VERSION 5.7 ;
  NOWIREEXTENSIONATPIN ON ;
  DIVIDERCHAR "/" ;
  BUSBITCHARS "[]" ;
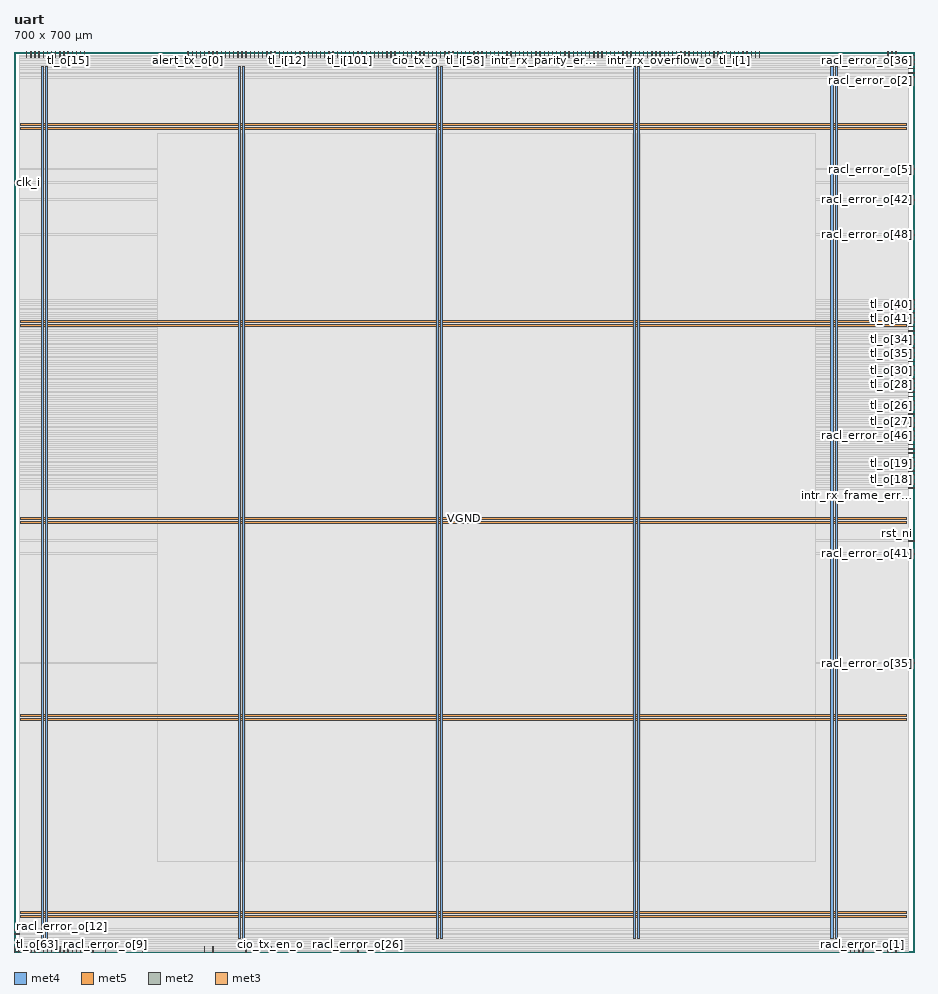
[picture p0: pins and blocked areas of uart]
MACRO uart
  CLASS BLOCK ;
  FOREIGN uart ;
  ORIGIN 0.000 0.000 ;
  SIZE 700.000 BY 700.000 ;
  PIN VGND
    DIRECTION INOUT ;
    USE GROUND ;
    PORT
      LAYER met4 ;
        RECT 24.340 10.640 25.940 688.400 ;
    END
    PORT
      LAYER met4 ;
        RECT 177.940 10.640 179.540 688.400 ;
    END
    PORT
      LAYER met4 ;
        RECT 331.540 10.640 333.140 688.400 ;
    END
    PORT
      LAYER met4 ;
        RECT 485.140 10.640 486.740 688.400 ;
    END
    PORT
      LAYER met4 ;
        RECT 638.740 10.640 640.340 688.400 ;
    END
    PORT
      LAYER met5 ;
        RECT 5.280 30.030 694.380 31.630 ;
    END
    PORT
      LAYER met5 ;
        RECT 5.280 183.210 694.380 184.810 ;
    END
    PORT
      LAYER met5 ;
        RECT 5.280 336.390 694.380 337.990 ;
    END
    PORT
      LAYER met5 ;
        RECT 5.280 489.570 694.380 491.170 ;
    END
    PORT
      LAYER met5 ;
        RECT 5.280 642.750 694.380 644.350 ;
    END
  END VGND
  PIN VPWR
    DIRECTION INOUT ;
    USE POWER ;
    PORT
      LAYER met4 ;
        RECT 21.040 10.640 22.640 688.400 ;
    END
    PORT
      LAYER met4 ;
        RECT 174.640 10.640 176.240 688.400 ;
    END
    PORT
      LAYER met4 ;
        RECT 328.240 10.640 329.840 688.400 ;
    END
    PORT
      LAYER met4 ;
        RECT 481.840 10.640 483.440 688.400 ;
    END
    PORT
      LAYER met4 ;
        RECT 635.440 10.640 637.040 688.400 ;
    END
    PORT
      LAYER met5 ;
        RECT 5.280 26.730 694.380 28.330 ;
    END
    PORT
      LAYER met5 ;
        RECT 5.280 179.910 694.380 181.510 ;
    END
    PORT
      LAYER met5 ;
        RECT 5.280 333.090 694.380 334.690 ;
    END
    PORT
      LAYER met5 ;
        RECT 5.280 486.270 694.380 487.870 ;
    END
    PORT
      LAYER met5 ;
        RECT 5.280 639.450 694.380 641.050 ;
    END
  END VPWR
  PIN alert_rx_i[0]
    DIRECTION INPUT ;
    USE SIGNAL ;
    ANTENNAGATEAREA 0.631200 ;
    ANTENNADIFFAREA 0.434700 ;
    PORT
      LAYER met2 ;
        RECT 19.410 696.000 19.690 700.000 ;
    END
  END alert_rx_i[0]
  PIN alert_rx_i[1]
    DIRECTION INPUT ;
    USE SIGNAL ;
    ANTENNAGATEAREA 0.631200 ;
    ANTENNADIFFAREA 0.434700 ;
    PORT
      LAYER met2 ;
        RECT 45.170 696.000 45.450 700.000 ;
    END
  END alert_rx_i[1]
  PIN alert_rx_i[2]
    DIRECTION INPUT ;
    USE SIGNAL ;
    ANTENNAGATEAREA 0.631200 ;
    ANTENNADIFFAREA 0.434700 ;
    PORT
      LAYER met2 ;
        RECT 54.830 696.000 55.110 700.000 ;
    END
  END alert_rx_i[2]
  PIN alert_rx_i[3]
    DIRECTION INPUT ;
    USE SIGNAL ;
    ANTENNAGATEAREA 0.631200 ;
    ANTENNADIFFAREA 0.434700 ;
    PORT
      LAYER met2 ;
        RECT 35.510 696.000 35.790 700.000 ;
    END
  END alert_rx_i[3]
  PIN alert_tx_o[0]
    DIRECTION OUTPUT ;
    USE SIGNAL ;
    ANTENNADIFFAREA 0.445500 ;
    PORT
      LAYER met2 ;
        RECT 135.330 696.000 135.610 700.000 ;
    END
  END alert_tx_o[0]
  PIN alert_tx_o[1]
    DIRECTION OUTPUT ;
    USE SIGNAL ;
    ANTENNADIFFAREA 0.445500 ;
    PORT
      LAYER met2 ;
        RECT 154.650 696.000 154.930 700.000 ;
    END
  END alert_tx_o[1]
  PIN cio_rx_i
    DIRECTION INPUT ;
    USE SIGNAL ;
    ANTENNAGATEAREA 0.647700 ;
    ANTENNADIFFAREA 0.434700 ;
    PORT
      LAYER met2 ;
        RECT 228.710 696.000 228.990 700.000 ;
    END
  END cio_rx_i
  PIN cio_tx_en_o
    DIRECTION OUTPUT ;
    USE SIGNAL ;
    PORT
      LAYER met2 ;
        RECT 199.730 0.000 200.010 4.000 ;
    END
  END cio_tx_en_o
  PIN cio_tx_o
    DIRECTION OUTPUT ;
    USE SIGNAL ;
    ANTENNADIFFAREA 0.445500 ;
    PORT
      LAYER met2 ;
        RECT 312.430 696.000 312.710 700.000 ;
    END
  END cio_tx_o
  PIN clk_i
    DIRECTION INPUT ;
    USE SIGNAL ;
    ANTENNAGATEAREA 0.682200 ;
    ANTENNADIFFAREA 0.434700 ;
    PORT
      LAYER met3 ;
        RECT 0.000 598.440 4.000 599.040 ;
    END
  END clk_i
  PIN intr_rx_break_err_o
    DIRECTION OUTPUT ;
    USE SIGNAL ;
    ANTENNADIFFAREA 0.445500 ;
    PORT
      LAYER met2 ;
        RECT 363.950 696.000 364.230 700.000 ;
    END
  END intr_rx_break_err_o
  PIN intr_rx_frame_err_o
    DIRECTION OUTPUT ;
    USE SIGNAL ;
    ANTENNADIFFAREA 0.445500 ;
    PORT
      LAYER met3 ;
        RECT 696.000 360.440 700.000 361.040 ;
    END
  END intr_rx_frame_err_o
  PIN intr_rx_overflow_o
    DIRECTION OUTPUT ;
    USE SIGNAL ;
    ANTENNADIFFAREA 0.445500 ;
    PORT
      LAYER met2 ;
        RECT 502.410 696.000 502.690 700.000 ;
    END
  END intr_rx_overflow_o
  PIN intr_rx_parity_err_o
    DIRECTION OUTPUT ;
    USE SIGNAL ;
    ANTENNADIFFAREA 0.445500 ;
    PORT
      LAYER met2 ;
        RECT 412.250 696.000 412.530 700.000 ;
    END
  END intr_rx_parity_err_o
  PIN intr_rx_timeout_o
    DIRECTION OUTPUT ;
    USE SIGNAL ;
    ANTENNADIFFAREA 0.445500 ;
    PORT
      LAYER met2 ;
        RECT 409.030 696.000 409.310 700.000 ;
    END
  END intr_rx_timeout_o
  PIN intr_rx_watermark_o
    DIRECTION OUTPUT ;
    USE SIGNAL ;
    ANTENNADIFFAREA 0.445500 ;
    PORT
      LAYER met3 ;
        RECT 696.000 370.640 700.000 371.240 ;
    END
  END intr_rx_watermark_o
  PIN intr_tx_done_o
    DIRECTION OUTPUT ;
    USE SIGNAL ;
    ANTENNADIFFAREA 0.445500 ;
    PORT
      LAYER met2 ;
        RECT 434.790 696.000 435.070 700.000 ;
    END
  END intr_tx_done_o
  PIN intr_tx_empty_o
    DIRECTION OUTPUT ;
    USE SIGNAL ;
    ANTENNADIFFAREA 0.445500 ;
    PORT
      LAYER met2 ;
        RECT 466.990 696.000 467.270 700.000 ;
    END
  END intr_tx_empty_o
  PIN intr_tx_watermark_o
    DIRECTION OUTPUT ;
    USE SIGNAL ;
    ANTENNADIFFAREA 0.445500 ;
    PORT
      LAYER met2 ;
        RECT 380.050 696.000 380.330 700.000 ;
    END
  END intr_tx_watermark_o
  PIN lsio_trigger_o
    DIRECTION OUTPUT ;
    USE SIGNAL ;
    ANTENNADIFFAREA 0.445500 ;
    PORT
      LAYER met3 ;
        RECT 696.000 377.440 700.000 378.040 ;
    END
  END lsio_trigger_o
  PIN racl_error_o[0]
    DIRECTION OUTPUT ;
    USE SIGNAL ;
    PORT
      LAYER met2 ;
        RECT 48.390 696.000 48.670 700.000 ;
    END
  END racl_error_o[0]
  PIN racl_error_o[10]
    DIRECTION OUTPUT ;
    USE SIGNAL ;
    PORT
      LAYER met3 ;
        RECT 696.000 697.040 700.000 697.640 ;
    END
  END racl_error_o[10]
  PIN racl_error_o[11]
    DIRECTION OUTPUT ;
    USE SIGNAL ;
    PORT
      LAYER met2 ;
        RECT 32.290 696.000 32.570 700.000 ;
    END
  END racl_error_o[11]
  PIN racl_error_o[12]
    DIRECTION OUTPUT ;
    USE SIGNAL ;
    PORT
      LAYER met3 ;
        RECT 0.000 13.640 4.000 14.240 ;
    END
  END racl_error_o[12]
  PIN racl_error_o[13]
    DIRECTION OUTPUT ;
    USE SIGNAL ;
    PORT
      LAYER met3 ;
        RECT 696.000 397.840 700.000 398.440 ;
    END
  END racl_error_o[13]
  PIN racl_error_o[14]
    DIRECTION OUTPUT ;
    USE SIGNAL ;
    PORT
      LAYER met2 ;
        RECT 251.250 0.000 251.530 4.000 ;
    END
  END racl_error_o[14]
  PIN racl_error_o[15]
    DIRECTION OUTPUT ;
    USE SIGNAL ;
    PORT
      LAYER met2 ;
        RECT 454.110 696.000 454.390 700.000 ;
    END
  END racl_error_o[15]
  PIN racl_error_o[16]
    DIRECTION OUTPUT ;
    USE SIGNAL ;
    PORT
      LAYER met2 ;
        RECT 180.410 0.000 180.690 4.000 ;
    END
  END racl_error_o[16]
  PIN racl_error_o[17]
    DIRECTION OUTPUT ;
    USE SIGNAL ;
    PORT
      LAYER met3 ;
        RECT 0.000 10.240 4.000 10.840 ;
    END
  END racl_error_o[17]
  PIN racl_error_o[18]
    DIRECTION OUTPUT ;
    USE SIGNAL ;
    PORT
      LAYER met2 ;
        RECT 29.070 696.000 29.350 700.000 ;
    END
  END racl_error_o[18]
  PIN racl_error_o[19]
    DIRECTION OUTPUT ;
    USE SIGNAL ;
    PORT
      LAYER met3 ;
        RECT 0.000 17.040 4.000 17.640 ;
    END
  END racl_error_o[19]
  PIN racl_error_o[1]
    DIRECTION OUTPUT ;
    USE SIGNAL ;
    PORT
      LAYER met2 ;
        RECT 660.190 0.000 660.470 4.000 ;
    END
  END racl_error_o[1]
  PIN racl_error_o[20]
    DIRECTION OUTPUT ;
    USE SIGNAL ;
    PORT
      LAYER met3 ;
        RECT 696.000 693.640 700.000 694.240 ;
    END
  END racl_error_o[20]
  PIN racl_error_o[21]
    DIRECTION OUTPUT ;
    USE SIGNAL ;
    ANTENNADIFFAREA 0.445500 ;
    PORT
      LAYER met2 ;
        RECT 512.070 696.000 512.350 700.000 ;
    END
  END racl_error_o[21]
  PIN racl_error_o[22]
    DIRECTION OUTPUT ;
    USE SIGNAL ;
    ANTENNADIFFAREA 0.445500 ;
    PORT
      LAYER met2 ;
        RECT 499.190 696.000 499.470 700.000 ;
    END
  END racl_error_o[22]
  PIN racl_error_o[23]
    DIRECTION OUTPUT ;
    USE SIGNAL ;
    ANTENNADIFFAREA 0.445500 ;
    PORT
      LAYER met2 ;
        RECT 402.590 696.000 402.870 700.000 ;
    END
  END racl_error_o[23]
  PIN racl_error_o[24]
    DIRECTION OUTPUT ;
    USE SIGNAL ;
    ANTENNADIFFAREA 0.445500 ;
    PORT
      LAYER met2 ;
        RECT 405.810 696.000 406.090 700.000 ;
    END
  END racl_error_o[24]
  PIN racl_error_o[25]
    DIRECTION OUTPUT ;
    USE SIGNAL ;
    PORT
      LAYER met3 ;
        RECT 696.000 680.040 700.000 680.640 ;
    END
  END racl_error_o[25]
  PIN racl_error_o[26]
    DIRECTION OUTPUT ;
    USE SIGNAL ;
    PORT
      LAYER met2 ;
        RECT 267.350 0.000 267.630 4.000 ;
    END
  END racl_error_o[26]
  PIN racl_error_o[27]
    DIRECTION OUTPUT ;
    USE SIGNAL ;
    PORT
      LAYER met3 ;
        RECT 696.000 686.840 700.000 687.440 ;
    END
  END racl_error_o[27]
  PIN racl_error_o[28]
    DIRECTION OUTPUT ;
    USE SIGNAL ;
    PORT
      LAYER met3 ;
        RECT 0.000 3.440 4.000 4.040 ;
    END
  END racl_error_o[28]
  PIN racl_error_o[29]
    DIRECTION OUTPUT ;
    USE SIGNAL ;
    PORT
      LAYER met3 ;
        RECT 0.000 6.840 4.000 7.440 ;
    END
  END racl_error_o[29]
  PIN racl_error_o[2]
    DIRECTION OUTPUT ;
    USE SIGNAL ;
    PORT
      LAYER met3 ;
        RECT 696.000 683.440 700.000 684.040 ;
    END
  END racl_error_o[2]
  PIN racl_error_o[30]
    DIRECTION OUTPUT ;
    USE SIGNAL ;
    PORT
      LAYER met3 ;
        RECT 0.000 0.040 4.000 0.640 ;
    END
  END racl_error_o[30]
  PIN racl_error_o[31]
    DIRECTION OUTPUT ;
    USE SIGNAL ;
    PORT
      LAYER met2 ;
        RECT 22.630 696.000 22.910 700.000 ;
    END
  END racl_error_o[31]
  PIN racl_error_o[32]
    DIRECTION OUTPUT ;
    USE SIGNAL ;
    PORT
      LAYER met3 ;
        RECT 696.000 690.240 700.000 690.840 ;
    END
  END racl_error_o[32]
  PIN racl_error_o[33]
    DIRECTION OUTPUT ;
    USE SIGNAL ;
    PORT
      LAYER met2 ;
        RECT 148.210 0.000 148.490 4.000 ;
    END
  END racl_error_o[33]
  PIN racl_error_o[34]
    DIRECTION OUTPUT ;
    USE SIGNAL ;
    PORT
      LAYER met2 ;
        RECT 19.410 0.000 19.690 4.000 ;
    END
  END racl_error_o[34]
  PIN racl_error_o[35]
    DIRECTION OUTPUT ;
    USE SIGNAL ;
    PORT
      LAYER met3 ;
        RECT 696.000 224.440 700.000 225.040 ;
    END
  END racl_error_o[35]
  PIN racl_error_o[36]
    DIRECTION OUTPUT ;
    USE SIGNAL ;
    PORT
      LAYER met2 ;
        RECT 679.510 696.000 679.790 700.000 ;
    END
  END racl_error_o[36]
  PIN racl_error_o[37]
    DIRECTION OUTPUT ;
    USE SIGNAL ;
    PORT
      LAYER met2 ;
        RECT 685.950 696.000 686.230 700.000 ;
    END
  END racl_error_o[37]
  PIN racl_error_o[38]
    DIRECTION OUTPUT ;
    USE SIGNAL ;
    PORT
      LAYER met2 ;
        RECT 650.530 0.000 650.810 4.000 ;
    END
  END racl_error_o[38]
  PIN racl_error_o[39]
    DIRECTION OUTPUT ;
    USE SIGNAL ;
    PORT
      LAYER met2 ;
        RECT 644.090 0.000 644.370 4.000 ;
    END
  END racl_error_o[39]
  PIN racl_error_o[3]
    DIRECTION OUTPUT ;
    USE SIGNAL ;
    PORT
      LAYER met2 ;
        RECT 679.510 0.000 679.790 4.000 ;
    END
  END racl_error_o[3]
  PIN racl_error_o[40]
    DIRECTION OUTPUT ;
    USE SIGNAL ;
    PORT
      LAYER met2 ;
        RECT 9.750 696.000 10.030 700.000 ;
    END
  END racl_error_o[40]
  PIN racl_error_o[41]
    DIRECTION OUTPUT ;
    USE SIGNAL ;
    PORT
      LAYER met3 ;
        RECT 696.000 309.440 700.000 310.040 ;
    END
  END racl_error_o[41]
  PIN racl_error_o[42]
    DIRECTION OUTPUT ;
    USE SIGNAL ;
    PORT
      LAYER met3 ;
        RECT 696.000 584.840 700.000 585.440 ;
    END
  END racl_error_o[42]
  PIN racl_error_o[43]
    DIRECTION OUTPUT ;
    USE SIGNAL ;
    PORT
      LAYER met2 ;
        RECT 647.310 0.000 647.590 4.000 ;
    END
  END racl_error_o[43]
  PIN racl_error_o[44]
    DIRECTION OUTPUT ;
    USE SIGNAL ;
    PORT
      LAYER met2 ;
        RECT 12.970 696.000 13.250 700.000 ;
    END
  END racl_error_o[44]
  PIN racl_error_o[45]
    DIRECTION OUTPUT ;
    USE SIGNAL ;
    PORT
      LAYER met2 ;
        RECT 653.750 0.000 654.030 4.000 ;
    END
  END racl_error_o[45]
  PIN racl_error_o[46]
    DIRECTION OUTPUT ;
    USE SIGNAL ;
    PORT
      LAYER met3 ;
        RECT 696.000 401.240 700.000 401.840 ;
    END
  END racl_error_o[46]
  PIN racl_error_o[47]
    DIRECTION OUTPUT ;
    USE SIGNAL ;
    PORT
      LAYER met2 ;
        RECT 99.910 0.000 100.190 4.000 ;
    END
  END racl_error_o[47]
  PIN racl_error_o[48]
    DIRECTION OUTPUT ;
    USE SIGNAL ;
    PORT
      LAYER met3 ;
        RECT 696.000 557.640 700.000 558.240 ;
    END
  END racl_error_o[48]
  PIN racl_error_o[49]
    DIRECTION OUTPUT ;
    USE SIGNAL ;
    PORT
      LAYER met2 ;
        RECT 557.150 696.000 557.430 700.000 ;
    END
  END racl_error_o[49]
  PIN racl_error_o[4]
    DIRECTION OUTPUT ;
    USE SIGNAL ;
    PORT
      LAYER met2 ;
        RECT 682.730 696.000 683.010 700.000 ;
    END
  END racl_error_o[4]
  PIN racl_error_o[50]
    DIRECTION OUTPUT ;
    USE SIGNAL ;
    PORT
      LAYER met2 ;
        RECT 656.970 0.000 657.250 4.000 ;
    END
  END racl_error_o[50]
  PIN racl_error_o[51]
    DIRECTION OUTPUT ;
    USE SIGNAL ;
    PORT
      LAYER met2 ;
        RECT 38.730 696.000 39.010 700.000 ;
    END
  END racl_error_o[51]
  PIN racl_error_o[5]
    DIRECTION OUTPUT ;
    USE SIGNAL ;
    PORT
      LAYER met3 ;
        RECT 696.000 608.640 700.000 609.240 ;
    END
  END racl_error_o[5]
  PIN racl_error_o[6]
    DIRECTION OUTPUT ;
    USE SIGNAL ;
    PORT
      LAYER met2 ;
        RECT 25.850 696.000 26.130 700.000 ;
    END
  END racl_error_o[6]
  PIN racl_error_o[7]
    DIRECTION OUTPUT ;
    USE SIGNAL ;
    PORT
      LAYER met2 ;
        RECT 51.610 696.000 51.890 700.000 ;
    END
  END racl_error_o[7]
  PIN racl_error_o[8]
    DIRECTION OUTPUT ;
    USE SIGNAL ;
    PORT
      LAYER met2 ;
        RECT 154.650 0.000 154.930 4.000 ;
    END
  END racl_error_o[8]
  PIN racl_error_o[9]
    DIRECTION OUTPUT ;
    USE SIGNAL ;
    PORT
      LAYER met2 ;
        RECT 70.930 0.000 71.210 4.000 ;
    END
  END racl_error_o[9]
  PIN racl_policies_i[0]
    DIRECTION INPUT ;
    USE SIGNAL ;
    PORT
      LAYER met2 ;
        RECT 3.310 0.000 3.590 4.000 ;
    END
  END racl_policies_i[0]
  PIN racl_policies_i[1]
    DIRECTION INPUT ;
    USE SIGNAL ;
    PORT
      LAYER met2 ;
        RECT 22.630 0.000 22.910 4.000 ;
    END
  END racl_policies_i[1]
  PIN racl_policies_i[2]
    DIRECTION INPUT ;
    USE SIGNAL ;
    PORT
      LAYER met2 ;
        RECT 6.530 0.000 6.810 4.000 ;
    END
  END racl_policies_i[2]
  PIN racl_policies_i[3]
    DIRECTION INPUT ;
    USE SIGNAL ;
    PORT
      LAYER met2 ;
        RECT 9.750 0.000 10.030 4.000 ;
    END
  END racl_policies_i[3]
  PIN racl_policies_i[4]
    DIRECTION INPUT ;
    USE SIGNAL ;
    PORT
      LAYER met2 ;
        RECT 32.290 0.000 32.570 4.000 ;
    END
  END racl_policies_i[4]
  PIN racl_policies_i[5]
    DIRECTION INPUT ;
    USE SIGNAL ;
    PORT
      LAYER met2 ;
        RECT 16.190 0.000 16.470 4.000 ;
    END
  END racl_policies_i[5]
  PIN racl_policies_i[6]
    DIRECTION INPUT ;
    USE SIGNAL ;
    PORT
      LAYER met2 ;
        RECT 29.070 0.000 29.350 4.000 ;
    END
  END racl_policies_i[6]
  PIN racl_policies_i[7]
    DIRECTION INPUT ;
    USE SIGNAL ;
    PORT
      LAYER met2 ;
        RECT 25.850 0.000 26.130 4.000 ;
    END
  END racl_policies_i[7]
  PIN rst_ni
    DIRECTION INPUT ;
    USE SIGNAL ;
    ANTENNAGATEAREA 0.631200 ;
    ANTENNADIFFAREA 0.434700 ;
    PORT
      LAYER met3 ;
        RECT 696.000 319.640 700.000 320.240 ;
    END
  END rst_ni
  PIN tl_i[0]
    DIRECTION INPUT ;
    USE SIGNAL ;
    ANTENNAGATEAREA 0.631200 ;
    ANTENNADIFFAREA 0.434700 ;
    PORT
      LAYER met2 ;
        RECT 318.870 696.000 319.150 700.000 ;
    END
  END tl_i[0]
  PIN tl_i[100]
    DIRECTION INPUT ;
    USE SIGNAL ;
    ANTENNAGATEAREA 0.631200 ;
    ANTENNADIFFAREA 0.434700 ;
    PORT
      LAYER met2 ;
        RECT 190.070 696.000 190.350 700.000 ;
    END
  END tl_i[100]
  PIN tl_i[101]
    DIRECTION INPUT ;
    USE SIGNAL ;
    ANTENNAGATEAREA 0.593700 ;
    ANTENNADIFFAREA 0.434700 ;
    PORT
      LAYER met2 ;
        RECT 260.910 696.000 261.190 700.000 ;
    END
  END tl_i[101]
  PIN tl_i[102]
    DIRECTION INPUT ;
    USE SIGNAL ;
    ANTENNAGATEAREA 0.593700 ;
    ANTENNADIFFAREA 0.434700 ;
    PORT
      LAYER met2 ;
        RECT 238.370 696.000 238.650 700.000 ;
    END
  END tl_i[102]
  PIN tl_i[103]
    DIRECTION INPUT ;
    USE SIGNAL ;
    PORT
      LAYER met2 ;
        RECT 35.510 0.000 35.790 4.000 ;
    END
  END tl_i[103]
  PIN tl_i[104]
    DIRECTION INPUT ;
    USE SIGNAL ;
    PORT
      LAYER met2 ;
        RECT 48.390 0.000 48.670 4.000 ;
    END
  END tl_i[104]
  PIN tl_i[105]
    DIRECTION INPUT ;
    USE SIGNAL ;
    PORT
      LAYER met2 ;
        RECT 41.950 0.000 42.230 4.000 ;
    END
  END tl_i[105]
  PIN tl_i[106]
    DIRECTION INPUT ;
    USE SIGNAL ;
    ANTENNAGATEAREA 0.631200 ;
    ANTENNADIFFAREA 0.434700 ;
    PORT
      LAYER met2 ;
        RECT 334.970 696.000 335.250 700.000 ;
    END
  END tl_i[106]
  PIN tl_i[107]
    DIRECTION INPUT ;
    USE SIGNAL ;
    ANTENNAGATEAREA 0.631200 ;
    ANTENNADIFFAREA 0.434700 ;
    PORT
      LAYER met2 ;
        RECT 376.830 696.000 377.110 700.000 ;
    END
  END tl_i[107]
  PIN tl_i[108]
    DIRECTION INPUT ;
    USE SIGNAL ;
    ANTENNAGATEAREA 0.560700 ;
    ANTENNADIFFAREA 0.434700 ;
    PORT
      LAYER met2 ;
        RECT 309.210 696.000 309.490 700.000 ;
    END
  END tl_i[108]
  PIN tl_i[109]
    DIRECTION INPUT ;
    USE SIGNAL ;
    ANTENNAGATEAREA 0.647700 ;
    ANTENNADIFFAREA 0.434700 ;
    PORT
      LAYER met2 ;
        RECT 325.310 696.000 325.590 700.000 ;
    END
  END tl_i[109]
  PIN tl_i[10]
    DIRECTION INPUT ;
    USE SIGNAL ;
    ANTENNAGATEAREA 0.631200 ;
    ANTENNADIFFAREA 0.434700 ;
    PORT
      LAYER met2 ;
        RECT 283.450 696.000 283.730 700.000 ;
    END
  END tl_i[10]
  PIN tl_i[11]
    DIRECTION INPUT ;
    USE SIGNAL ;
    ANTENNAGATEAREA 0.631200 ;
    ANTENNADIFFAREA 0.434700 ;
    PORT
      LAYER met2 ;
        RECT 370.390 696.000 370.670 700.000 ;
    END
  END tl_i[11]
  PIN tl_i[12]
    DIRECTION INPUT ;
    USE SIGNAL ;
    ANTENNAGATEAREA 0.631200 ;
    ANTENNADIFFAREA 0.434700 ;
    PORT
      LAYER met2 ;
        RECT 212.610 696.000 212.890 700.000 ;
    END
  END tl_i[12]
  PIN tl_i[13]
    DIRECTION INPUT ;
    USE SIGNAL ;
    ANTENNAGATEAREA 0.631200 ;
    ANTENNADIFFAREA 0.434700 ;
    PORT
      LAYER met2 ;
        RECT 244.810 696.000 245.090 700.000 ;
    END
  END tl_i[13]
  PIN tl_i[14]
    DIRECTION INPUT ;
    USE SIGNAL ;
    ANTENNAGATEAREA 0.631200 ;
    ANTENNADIFFAREA 0.434700 ;
    PORT
      LAYER met2 ;
        RECT 180.410 696.000 180.690 700.000 ;
    END
  END tl_i[14]
  PIN tl_i[15]
    DIRECTION INPUT ;
    USE SIGNAL ;
    ANTENNAGATEAREA 0.647700 ;
    ANTENNADIFFAREA 0.434700 ;
    PORT
      LAYER met2 ;
        RECT 225.490 696.000 225.770 700.000 ;
    END
  END tl_i[15]
  PIN tl_i[16]
    DIRECTION INPUT ;
    USE SIGNAL ;
    ANTENNAGATEAREA 0.631200 ;
    ANTENNADIFFAREA 0.434700 ;
    PORT
      LAYER met2 ;
        RECT 254.470 696.000 254.750 700.000 ;
    END
  END tl_i[16]
  PIN tl_i[17]
    DIRECTION INPUT ;
    USE SIGNAL ;
    ANTENNAGATEAREA 0.631200 ;
    ANTENNADIFFAREA 0.434700 ;
    PORT
      LAYER met2 ;
        RECT 235.150 696.000 235.430 700.000 ;
    END
  END tl_i[17]
  PIN tl_i[18]
    DIRECTION INPUT ;
    USE SIGNAL ;
    ANTENNAGATEAREA 0.631200 ;
    ANTENNADIFFAREA 0.434700 ;
    PORT
      LAYER met2 ;
        RECT 277.010 696.000 277.290 700.000 ;
    END
  END tl_i[18]
  PIN tl_i[19]
    DIRECTION INPUT ;
    USE SIGNAL ;
    PORT
      LAYER met2 ;
        RECT 38.730 0.000 39.010 4.000 ;
    END
  END tl_i[19]
  PIN tl_i[1]
    DIRECTION INPUT ;
    USE SIGNAL ;
    ANTENNAGATEAREA 0.631200 ;
    ANTENNADIFFAREA 0.434700 ;
    PORT
      LAYER met2 ;
        RECT 560.370 696.000 560.650 700.000 ;
    END
  END tl_i[1]
  PIN tl_i[20]
    DIRECTION INPUT ;
    USE SIGNAL ;
    PORT
      LAYER met2 ;
        RECT 61.270 0.000 61.550 4.000 ;
    END
  END tl_i[20]
  PIN tl_i[21]
    DIRECTION INPUT ;
    USE SIGNAL ;
    PORT
      LAYER met2 ;
        RECT 45.170 0.000 45.450 4.000 ;
    END
  END tl_i[21]
  PIN tl_i[22]
    DIRECTION INPUT ;
    USE SIGNAL ;
    PORT
      LAYER met2 ;
        RECT 58.050 0.000 58.330 4.000 ;
    END
  END tl_i[22]
  PIN tl_i[23]
    DIRECTION INPUT ;
    USE SIGNAL ;
    PORT
      LAYER met2 ;
        RECT 0.090 0.000 0.370 4.000 ;
    END
  END tl_i[23]
  PIN tl_i[24]
    DIRECTION INPUT ;
    USE SIGNAL ;
    PORT
      LAYER met2 ;
        RECT 54.830 0.000 55.110 4.000 ;
    END
  END tl_i[24]
  PIN tl_i[25]
    DIRECTION INPUT ;
    USE SIGNAL ;
    ANTENNAGATEAREA 0.631200 ;
    ANTENNADIFFAREA 0.434700 ;
    PORT
      LAYER met2 ;
        RECT 418.690 696.000 418.970 700.000 ;
    END
  END tl_i[25]
  PIN tl_i[26]
    DIRECTION INPUT ;
    USE SIGNAL ;
    ANTENNAGATEAREA 0.631200 ;
    ANTENNADIFFAREA 0.434700 ;
    PORT
      LAYER met2 ;
        RECT 441.230 696.000 441.510 700.000 ;
    END
  END tl_i[26]
  PIN tl_i[27]
    DIRECTION INPUT ;
    USE SIGNAL ;
    ANTENNAGATEAREA 0.631200 ;
    ANTENNADIFFAREA 0.434700 ;
    PORT
      LAYER met2 ;
        RECT 431.570 696.000 431.850 700.000 ;
    END
  END tl_i[27]
  PIN tl_i[28]
    DIRECTION INPUT ;
    USE SIGNAL ;
    ANTENNAGATEAREA 0.631200 ;
    ANTENNADIFFAREA 0.434700 ;
    PORT
      LAYER met2 ;
        RECT 438.010 696.000 438.290 700.000 ;
    END
  END tl_i[28]
  PIN tl_i[29]
    DIRECTION INPUT ;
    USE SIGNAL ;
    ANTENNAGATEAREA 0.593700 ;
    ANTENNADIFFAREA 0.434700 ;
    PORT
      LAYER met2 ;
        RECT 421.910 696.000 422.190 700.000 ;
    END
  END tl_i[29]
  PIN tl_i[2]
    DIRECTION INPUT ;
    USE SIGNAL ;
    ANTENNAGATEAREA 0.631200 ;
    ANTENNADIFFAREA 0.434700 ;
    PORT
      LAYER met2 ;
        RECT 425.130 696.000 425.410 700.000 ;
    END
  END tl_i[2]
  PIN tl_i[30]
    DIRECTION INPUT ;
    USE SIGNAL ;
    ANTENNAGATEAREA 0.647700 ;
    ANTENNADIFFAREA 0.434700 ;
    PORT
      LAYER met2 ;
        RECT 457.330 696.000 457.610 700.000 ;
    END
  END tl_i[30]
  PIN tl_i[31]
    DIRECTION INPUT ;
    USE SIGNAL ;
    ANTENNAGATEAREA 0.647700 ;
    ANTENNADIFFAREA 0.434700 ;
    PORT
      LAYER met2 ;
        RECT 141.770 696.000 142.050 700.000 ;
    END
  END tl_i[31]
  PIN tl_i[32]
    DIRECTION INPUT ;
    USE SIGNAL ;
    ANTENNAGATEAREA 0.631200 ;
    ANTENNADIFFAREA 0.434700 ;
    PORT
      LAYER met2 ;
        RECT 447.670 696.000 447.950 700.000 ;
    END
  END tl_i[32]
  PIN tl_i[33]
    DIRECTION INPUT ;
    USE SIGNAL ;
    ANTENNAGATEAREA 0.560700 ;
    ANTENNADIFFAREA 0.434700 ;
    PORT
      LAYER met2 ;
        RECT 470.210 696.000 470.490 700.000 ;
    END
  END tl_i[33]
  PIN tl_i[34]
    DIRECTION INPUT ;
    USE SIGNAL ;
    ANTENNAGATEAREA 0.631200 ;
    ANTENNADIFFAREA 0.434700 ;
    PORT
      LAYER met2 ;
        RECT 460.550 696.000 460.830 700.000 ;
    END
  END tl_i[34]
  PIN tl_i[35]
    DIRECTION INPUT ;
    USE SIGNAL ;
    ANTENNAGATEAREA 0.631200 ;
    ANTENNADIFFAREA 0.434700 ;
    PORT
      LAYER met2 ;
        RECT 479.870 696.000 480.150 700.000 ;
    END
  END tl_i[35]
  PIN tl_i[36]
    DIRECTION INPUT ;
    USE SIGNAL ;
    ANTENNAGATEAREA 0.647700 ;
    ANTENNADIFFAREA 0.434700 ;
    PORT
      LAYER met2 ;
        RECT 444.450 696.000 444.730 700.000 ;
    END
  END tl_i[36]
  PIN tl_i[37]
    DIRECTION INPUT ;
    USE SIGNAL ;
    ANTENNAGATEAREA 0.560700 ;
    ANTENNADIFFAREA 0.434700 ;
    PORT
      LAYER met2 ;
        RECT 489.530 696.000 489.810 700.000 ;
    END
  END tl_i[37]
  PIN tl_i[38]
    DIRECTION INPUT ;
    USE SIGNAL ;
    ANTENNAGATEAREA 0.631200 ;
    ANTENNADIFFAREA 0.434700 ;
    PORT
      LAYER met2 ;
        RECT 463.770 696.000 464.050 700.000 ;
    END
  END tl_i[38]
  PIN tl_i[39]
    DIRECTION INPUT ;
    USE SIGNAL ;
    ANTENNAGATEAREA 0.631200 ;
    ANTENNADIFFAREA 0.434700 ;
    PORT
      LAYER met2 ;
        RECT 492.750 696.000 493.030 700.000 ;
    END
  END tl_i[39]
  PIN tl_i[3]
    DIRECTION INPUT ;
    USE SIGNAL ;
    ANTENNAGATEAREA 0.631200 ;
    ANTENNADIFFAREA 0.434700 ;
    PORT
      LAYER met2 ;
        RECT 476.650 696.000 476.930 700.000 ;
    END
  END tl_i[3]
  PIN tl_i[40]
    DIRECTION INPUT ;
    USE SIGNAL ;
    ANTENNAGATEAREA 0.593700 ;
    ANTENNADIFFAREA 0.434700 ;
    PORT
      LAYER met2 ;
        RECT 486.310 696.000 486.590 700.000 ;
    END
  END tl_i[40]
  PIN tl_i[41]
    DIRECTION INPUT ;
    USE SIGNAL ;
    ANTENNAGATEAREA 0.631200 ;
    ANTENNADIFFAREA 0.434700 ;
    PORT
      LAYER met2 ;
        RECT 515.290 696.000 515.570 700.000 ;
    END
  END tl_i[41]
  PIN tl_i[42]
    DIRECTION INPUT ;
    USE SIGNAL ;
    ANTENNAGATEAREA 0.631200 ;
    ANTENNADIFFAREA 0.434700 ;
    PORT
      LAYER met2 ;
        RECT 524.950 696.000 525.230 700.000 ;
    END
  END tl_i[42]
  PIN tl_i[43]
    DIRECTION INPUT ;
    USE SIGNAL ;
    ANTENNAGATEAREA 0.647700 ;
    ANTENNADIFFAREA 0.434700 ;
    PORT
      LAYER met2 ;
        RECT 531.390 696.000 531.670 700.000 ;
    END
  END tl_i[43]
  PIN tl_i[44]
    DIRECTION INPUT ;
    USE SIGNAL ;
    ANTENNAGATEAREA 0.631200 ;
    ANTENNADIFFAREA 0.434700 ;
    PORT
      LAYER met2 ;
        RECT 528.170 696.000 528.450 700.000 ;
    END
  END tl_i[44]
  PIN tl_i[45]
    DIRECTION INPUT ;
    USE SIGNAL ;
    ANTENNAGATEAREA 0.593700 ;
    ANTENNADIFFAREA 0.434700 ;
    PORT
      LAYER met2 ;
        RECT 547.490 696.000 547.770 700.000 ;
    END
  END tl_i[45]
  PIN tl_i[46]
    DIRECTION INPUT ;
    USE SIGNAL ;
    ANTENNAGATEAREA 0.560700 ;
    ANTENNADIFFAREA 0.434700 ;
    PORT
      LAYER met2 ;
        RECT 521.730 696.000 522.010 700.000 ;
    END
  END tl_i[46]
  PIN tl_i[47]
    DIRECTION INPUT ;
    USE SIGNAL ;
    ANTENNAGATEAREA 0.631200 ;
    ANTENNADIFFAREA 0.434700 ;
    PORT
      LAYER met2 ;
        RECT 534.610 696.000 534.890 700.000 ;
    END
  END tl_i[47]
  PIN tl_i[48]
    DIRECTION INPUT ;
    USE SIGNAL ;
    ANTENNAGATEAREA 0.560700 ;
    ANTENNADIFFAREA 0.434700 ;
    PORT
      LAYER met2 ;
        RECT 537.830 696.000 538.110 700.000 ;
    END
  END tl_i[48]
  PIN tl_i[49]
    DIRECTION INPUT ;
    USE SIGNAL ;
    ANTENNAGATEAREA 0.631200 ;
    ANTENNADIFFAREA 0.434700 ;
    PORT
      LAYER met2 ;
        RECT 553.930 696.000 554.210 700.000 ;
    END
  END tl_i[49]
  PIN tl_i[4]
    DIRECTION INPUT ;
    USE SIGNAL ;
    ANTENNAGATEAREA 0.631200 ;
    ANTENNADIFFAREA 0.434700 ;
    PORT
      LAYER met2 ;
        RECT 450.890 696.000 451.170 700.000 ;
    END
  END tl_i[4]
  PIN tl_i[50]
    DIRECTION INPUT ;
    USE SIGNAL ;
    ANTENNAGATEAREA 0.631200 ;
    ANTENNADIFFAREA 0.434700 ;
    PORT
      LAYER met2 ;
        RECT 579.690 696.000 579.970 700.000 ;
    END
  END tl_i[50]
  PIN tl_i[51]
    DIRECTION INPUT ;
    USE SIGNAL ;
    ANTENNAGATEAREA 0.631200 ;
    ANTENNADIFFAREA 0.434700 ;
    PORT
      LAYER met2 ;
        RECT 570.030 696.000 570.310 700.000 ;
    END
  END tl_i[51]
  PIN tl_i[52]
    DIRECTION INPUT ;
    USE SIGNAL ;
    ANTENNAGATEAREA 0.631200 ;
    ANTENNADIFFAREA 0.434700 ;
    PORT
      LAYER met2 ;
        RECT 566.810 696.000 567.090 700.000 ;
    END
  END tl_i[52]
  PIN tl_i[53]
    DIRECTION INPUT ;
    USE SIGNAL ;
    ANTENNAGATEAREA 0.631200 ;
    ANTENNADIFFAREA 0.434700 ;
    PORT
      LAYER met2 ;
        RECT 541.050 696.000 541.330 700.000 ;
    END
  END tl_i[53]
  PIN tl_i[54]
    DIRECTION INPUT ;
    USE SIGNAL ;
    ANTENNAGATEAREA 0.647700 ;
    ANTENNADIFFAREA 0.434700 ;
    PORT
      LAYER met2 ;
        RECT 563.590 696.000 563.870 700.000 ;
    END
  END tl_i[54]
  PIN tl_i[55]
    DIRECTION INPUT ;
    USE SIGNAL ;
    ANTENNAGATEAREA 0.631200 ;
    ANTENNADIFFAREA 0.434700 ;
    PORT
      LAYER met2 ;
        RECT 550.710 696.000 550.990 700.000 ;
    END
  END tl_i[55]
  PIN tl_i[56]
    DIRECTION INPUT ;
    USE SIGNAL ;
    ANTENNAGATEAREA 0.631200 ;
    ANTENNADIFFAREA 0.434700 ;
    PORT
      LAYER met2 ;
        RECT 544.270 696.000 544.550 700.000 ;
    END
  END tl_i[56]
  PIN tl_i[57]
    DIRECTION INPUT ;
    USE SIGNAL ;
    ANTENNAGATEAREA 0.631200 ;
    ANTENNADIFFAREA 0.434700 ;
    PORT
      LAYER met2 ;
        RECT 341.410 696.000 341.690 700.000 ;
    END
  END tl_i[57]
  PIN tl_i[58]
    DIRECTION INPUT ;
    USE SIGNAL ;
    ANTENNAGATEAREA 0.560700 ;
    ANTENNADIFFAREA 0.434700 ;
    PORT
      LAYER met2 ;
        RECT 351.070 696.000 351.350 700.000 ;
    END
  END tl_i[58]
  PIN tl_i[59]
    DIRECTION INPUT ;
    USE SIGNAL ;
    ANTENNAGATEAREA 0.631200 ;
    ANTENNADIFFAREA 0.434700 ;
    PORT
      LAYER met2 ;
        RECT 354.290 696.000 354.570 700.000 ;
    END
  END tl_i[59]
  PIN tl_i[5]
    DIRECTION INPUT ;
    USE SIGNAL ;
    ANTENNAGATEAREA 0.631200 ;
    ANTENNADIFFAREA 0.434700 ;
    PORT
      LAYER met2 ;
        RECT 518.510 696.000 518.790 700.000 ;
    END
  END tl_i[5]
  PIN tl_i[60]
    DIRECTION INPUT ;
    USE SIGNAL ;
    ANTENNAGATEAREA 0.631200 ;
    ANTENNADIFFAREA 0.434700 ;
    PORT
      LAYER met2 ;
        RECT 508.850 696.000 509.130 700.000 ;
    END
  END tl_i[60]
  PIN tl_i[61]
    DIRECTION INPUT ;
    USE SIGNAL ;
    ANTENNAGATEAREA 0.631200 ;
    ANTENNADIFFAREA 0.434700 ;
    PORT
      LAYER met2 ;
        RECT 383.270 696.000 383.550 700.000 ;
    END
  END tl_i[61]
  PIN tl_i[62]
    DIRECTION INPUT ;
    USE SIGNAL ;
    ANTENNAGATEAREA 0.631200 ;
    ANTENNADIFFAREA 0.434700 ;
    PORT
      LAYER met2 ;
        RECT 344.630 696.000 344.910 700.000 ;
    END
  END tl_i[62]
  PIN tl_i[63]
    DIRECTION INPUT ;
    USE SIGNAL ;
    ANTENNAGATEAREA 0.647700 ;
    ANTENNADIFFAREA 0.434700 ;
    PORT
      LAYER met2 ;
        RECT 386.490 696.000 386.770 700.000 ;
    END
  END tl_i[63]
  PIN tl_i[64]
    DIRECTION INPUT ;
    USE SIGNAL ;
    ANTENNAGATEAREA 0.631200 ;
    ANTENNADIFFAREA 0.434700 ;
    PORT
      LAYER met2 ;
        RECT 483.090 696.000 483.370 700.000 ;
    END
  END tl_i[64]
  PIN tl_i[65]
    DIRECTION INPUT ;
    USE SIGNAL ;
    ANTENNAGATEAREA 0.631200 ;
    ANTENNADIFFAREA 0.434700 ;
    PORT
      LAYER met2 ;
        RECT 576.470 696.000 576.750 700.000 ;
    END
  END tl_i[65]
  PIN tl_i[66]
    DIRECTION INPUT ;
    USE SIGNAL ;
    ANTENNAGATEAREA 0.631200 ;
    ANTENNADIFFAREA 0.434700 ;
    PORT
      LAYER met2 ;
        RECT 573.250 696.000 573.530 700.000 ;
    END
  END tl_i[66]
  PIN tl_i[67]
    DIRECTION INPUT ;
    USE SIGNAL ;
    ANTENNAGATEAREA 0.593700 ;
    ANTENNADIFFAREA 0.434700 ;
    PORT
      LAYER met2 ;
        RECT 360.730 696.000 361.010 700.000 ;
    END
  END tl_i[67]
  PIN tl_i[68]
    DIRECTION INPUT ;
    USE SIGNAL ;
    ANTENNAGATEAREA 0.631200 ;
    ANTENNADIFFAREA 0.434700 ;
    PORT
      LAYER met2 ;
        RECT 495.970 696.000 496.250 700.000 ;
    END
  END tl_i[68]
  PIN tl_i[69]
    DIRECTION INPUT ;
    USE SIGNAL ;
    ANTENNAGATEAREA 0.647700 ;
    ANTENNADIFFAREA 0.434700 ;
    PORT
      LAYER met2 ;
        RECT 505.630 696.000 505.910 700.000 ;
    END
  END tl_i[69]
  PIN tl_i[6]
    DIRECTION INPUT ;
    USE SIGNAL ;
    ANTENNAGATEAREA 0.631200 ;
    ANTENNADIFFAREA 0.434700 ;
    PORT
      LAYER met2 ;
        RECT 473.430 696.000 473.710 700.000 ;
    END
  END tl_i[6]
  PIN tl_i[70]
    DIRECTION INPUT ;
    USE SIGNAL ;
    ANTENNAGATEAREA 0.647700 ;
    ANTENNADIFFAREA 0.434700 ;
    PORT
      LAYER met2 ;
        RECT 299.550 696.000 299.830 700.000 ;
    END
  END tl_i[70]
  PIN tl_i[71]
    DIRECTION INPUT ;
    USE SIGNAL ;
    ANTENNAGATEAREA 0.647700 ;
    ANTENNADIFFAREA 0.434700 ;
    PORT
      LAYER met2 ;
        RECT 357.510 696.000 357.790 700.000 ;
    END
  END tl_i[71]
  PIN tl_i[72]
    DIRECTION INPUT ;
    USE SIGNAL ;
    ANTENNAGATEAREA 0.631200 ;
    ANTENNADIFFAREA 0.434700 ;
    PORT
      LAYER met2 ;
        RECT 331.750 696.000 332.030 700.000 ;
    END
  END tl_i[72]
  PIN tl_i[73]
    DIRECTION INPUT ;
    USE SIGNAL ;
    ANTENNAGATEAREA 0.647700 ;
    ANTENNADIFFAREA 0.434700 ;
    PORT
      LAYER met2 ;
        RECT 144.990 696.000 145.270 700.000 ;
    END
  END tl_i[73]
  PIN tl_i[74]
    DIRECTION INPUT ;
    USE SIGNAL ;
    ANTENNAGATEAREA 0.647700 ;
    ANTENNADIFFAREA 0.434700 ;
    PORT
      LAYER met2 ;
        RECT 328.530 696.000 328.810 700.000 ;
    END
  END tl_i[74]
  PIN tl_i[75]
    DIRECTION INPUT ;
    USE SIGNAL ;
    ANTENNAGATEAREA 0.560700 ;
    ANTENNADIFFAREA 0.434700 ;
    PORT
      LAYER met2 ;
        RECT 302.770 696.000 303.050 700.000 ;
    END
  END tl_i[75]
  PIN tl_i[76]
    DIRECTION INPUT ;
    USE SIGNAL ;
    ANTENNAGATEAREA 0.560700 ;
    ANTENNADIFFAREA 0.434700 ;
    PORT
      LAYER met2 ;
        RECT 305.990 696.000 306.270 700.000 ;
    END
  END tl_i[76]
  PIN tl_i[77]
    DIRECTION INPUT ;
    USE SIGNAL ;
    ANTENNAGATEAREA 0.593700 ;
    ANTENNADIFFAREA 0.434700 ;
    PORT
      LAYER met2 ;
        RECT 193.290 696.000 193.570 700.000 ;
    END
  END tl_i[77]
  PIN tl_i[78]
    DIRECTION INPUT ;
    USE SIGNAL ;
    ANTENNAGATEAREA 0.631200 ;
    ANTENNADIFFAREA 0.434700 ;
    PORT
      LAYER met2 ;
        RECT 347.850 696.000 348.130 700.000 ;
    END
  END tl_i[78]
  PIN tl_i[79]
    DIRECTION INPUT ;
    USE SIGNAL ;
    ANTENNAGATEAREA 0.631200 ;
    ANTENNADIFFAREA 0.434700 ;
    PORT
      LAYER met2 ;
        RECT 389.710 696.000 389.990 700.000 ;
    END
  END tl_i[79]
  PIN tl_i[7]
    DIRECTION INPUT ;
    USE SIGNAL ;
    ANTENNAGATEAREA 0.631200 ;
    ANTENNADIFFAREA 0.434700 ;
    PORT
      LAYER met2 ;
        RECT 415.470 696.000 415.750 700.000 ;
    END
  END tl_i[7]
  PIN tl_i[80]
    DIRECTION INPUT ;
    USE SIGNAL ;
    ANTENNAGATEAREA 0.560700 ;
    ANTENNADIFFAREA 0.434700 ;
    PORT
      LAYER met2 ;
        RECT 367.170 696.000 367.450 700.000 ;
    END
  END tl_i[80]
  PIN tl_i[81]
    DIRECTION INPUT ;
    USE SIGNAL ;
    ANTENNAGATEAREA 0.647700 ;
    ANTENNADIFFAREA 0.434700 ;
    PORT
      LAYER met2 ;
        RECT 373.610 696.000 373.890 700.000 ;
    END
  END tl_i[81]
  PIN tl_i[82]
    DIRECTION INPUT ;
    USE SIGNAL ;
    ANTENNAGATEAREA 0.631200 ;
    ANTENNADIFFAREA 0.434700 ;
    PORT
      LAYER met2 ;
        RECT 392.930 696.000 393.210 700.000 ;
    END
  END tl_i[82]
  PIN tl_i[83]
    DIRECTION INPUT ;
    USE SIGNAL ;
    ANTENNAGATEAREA 0.631200 ;
    ANTENNADIFFAREA 0.434700 ;
    PORT
      LAYER met2 ;
        RECT 396.150 696.000 396.430 700.000 ;
    END
  END tl_i[83]
  PIN tl_i[84]
    DIRECTION INPUT ;
    USE SIGNAL ;
    ANTENNAGATEAREA 0.647700 ;
    ANTENNADIFFAREA 0.434700 ;
    PORT
      LAYER met2 ;
        RECT 399.370 696.000 399.650 700.000 ;
    END
  END tl_i[84]
  PIN tl_i[85]
    DIRECTION INPUT ;
    USE SIGNAL ;
    ANTENNAGATEAREA 0.631200 ;
    ANTENNADIFFAREA 0.434700 ;
    PORT
      LAYER met2 ;
        RECT 428.350 696.000 428.630 700.000 ;
    END
  END tl_i[85]
  PIN tl_i[86]
    DIRECTION INPUT ;
    USE SIGNAL ;
    ANTENNAGATEAREA 0.631200 ;
    ANTENNADIFFAREA 0.434700 ;
    PORT
      LAYER met2 ;
        RECT 173.970 696.000 174.250 700.000 ;
    END
  END tl_i[86]
  PIN tl_i[87]
    DIRECTION INPUT ;
    USE SIGNAL ;
    ANTENNAGATEAREA 0.631200 ;
    ANTENNADIFFAREA 0.434700 ;
    PORT
      LAYER met2 ;
        RECT 202.950 696.000 203.230 700.000 ;
    END
  END tl_i[87]
  PIN tl_i[88]
    DIRECTION INPUT ;
    USE SIGNAL ;
    ANTENNAGATEAREA 0.631200 ;
    ANTENNADIFFAREA 0.434700 ;
    PORT
      LAYER met2 ;
        RECT 151.430 696.000 151.710 700.000 ;
    END
  END tl_i[88]
  PIN tl_i[89]
    DIRECTION INPUT ;
    USE SIGNAL ;
    ANTENNAGATEAREA 0.631200 ;
    ANTENNADIFFAREA 0.434700 ;
    PORT
      LAYER met2 ;
        RECT 196.510 696.000 196.790 700.000 ;
    END
  END tl_i[89]
  PIN tl_i[8]
    DIRECTION INPUT ;
    USE SIGNAL ;
    ANTENNAGATEAREA 0.631200 ;
    ANTENNADIFFAREA 0.434700 ;
    PORT
      LAYER met2 ;
        RECT 315.650 696.000 315.930 700.000 ;
    END
  END tl_i[8]
  PIN tl_i[90]
    DIRECTION INPUT ;
    USE SIGNAL ;
    ANTENNAGATEAREA 0.631200 ;
    ANTENNADIFFAREA 0.434700 ;
    PORT
      LAYER met2 ;
        RECT 183.630 696.000 183.910 700.000 ;
    END
  END tl_i[90]
  PIN tl_i[91]
    DIRECTION INPUT ;
    USE SIGNAL ;
    ANTENNAGATEAREA 0.647700 ;
    ANTENNADIFFAREA 0.434700 ;
    PORT
      LAYER met2 ;
        RECT 222.270 696.000 222.550 700.000 ;
    END
  END tl_i[91]
  PIN tl_i[92]
    DIRECTION INPUT ;
    USE SIGNAL ;
    ANTENNAGATEAREA 0.631200 ;
    ANTENNADIFFAREA 0.434700 ;
    PORT
      LAYER met2 ;
        RECT 209.390 696.000 209.670 700.000 ;
    END
  END tl_i[92]
  PIN tl_i[93]
    DIRECTION INPUT ;
    USE SIGNAL ;
    ANTENNAGATEAREA 0.631200 ;
    ANTENNADIFFAREA 0.434700 ;
    PORT
      LAYER met2 ;
        RECT 215.830 696.000 216.110 700.000 ;
    END
  END tl_i[93]
  PIN tl_i[94]
    DIRECTION INPUT ;
    USE SIGNAL ;
    ANTENNAGATEAREA 0.631200 ;
    ANTENNADIFFAREA 0.434700 ;
    PORT
      LAYER met2 ;
        RECT 251.250 696.000 251.530 700.000 ;
    END
  END tl_i[94]
  PIN tl_i[95]
    DIRECTION INPUT ;
    USE SIGNAL ;
    ANTENNAGATEAREA 0.631200 ;
    ANTENNADIFFAREA 0.434700 ;
    PORT
      LAYER met2 ;
        RECT 248.030 696.000 248.310 700.000 ;
    END
  END tl_i[95]
  PIN tl_i[96]
    DIRECTION INPUT ;
    USE SIGNAL ;
    ANTENNAGATEAREA 0.631200 ;
    ANTENNADIFFAREA 0.434700 ;
    PORT
      LAYER met2 ;
        RECT 167.530 696.000 167.810 700.000 ;
    END
  END tl_i[96]
  PIN tl_i[97]
    DIRECTION INPUT ;
    USE SIGNAL ;
    ANTENNAGATEAREA 0.631200 ;
    ANTENNADIFFAREA 0.434700 ;
    PORT
      LAYER met2 ;
        RECT 170.750 696.000 171.030 700.000 ;
    END
  END tl_i[97]
  PIN tl_i[98]
    DIRECTION INPUT ;
    USE SIGNAL ;
    ANTENNAGATEAREA 0.631200 ;
    ANTENNADIFFAREA 0.434700 ;
    PORT
      LAYER met2 ;
        RECT 206.170 696.000 206.450 700.000 ;
    END
  END tl_i[98]
  PIN tl_i[99]
    DIRECTION INPUT ;
    USE SIGNAL ;
    ANTENNAGATEAREA 0.631200 ;
    ANTENNADIFFAREA 0.434700 ;
    PORT
      LAYER met2 ;
        RECT 257.690 696.000 257.970 700.000 ;
    END
  END tl_i[99]
  PIN tl_i[9]
    DIRECTION INPUT ;
    USE SIGNAL ;
    ANTENNAGATEAREA 0.631200 ;
    ANTENNADIFFAREA 0.434700 ;
    PORT
      LAYER met2 ;
        RECT 267.350 696.000 267.630 700.000 ;
    END
  END tl_i[9]
  PIN tl_o[0]
    DIRECTION OUTPUT ;
    USE SIGNAL ;
    ANTENNADIFFAREA 0.445500 ;
    PORT
      LAYER met2 ;
        RECT 322.090 696.000 322.370 700.000 ;
    END
  END tl_o[0]
  PIN tl_o[10]
    DIRECTION OUTPUT ;
    USE SIGNAL ;
    ANTENNADIFFAREA 0.445500 ;
    PORT
      LAYER met2 ;
        RECT 296.330 696.000 296.610 700.000 ;
    END
  END tl_o[10]
  PIN tl_o[11]
    DIRECTION OUTPUT ;
    USE SIGNAL ;
    ANTENNADIFFAREA 0.445500 ;
    PORT
      LAYER met2 ;
        RECT 231.930 696.000 232.210 700.000 ;
    END
  END tl_o[11]
  PIN tl_o[12]
    DIRECTION OUTPUT ;
    USE SIGNAL ;
    ANTENNADIFFAREA 0.445500 ;
    PORT
      LAYER met2 ;
        RECT 157.870 696.000 158.150 700.000 ;
    END
  END tl_o[12]
  PIN tl_o[13]
    DIRECTION OUTPUT ;
    USE SIGNAL ;
    ANTENNADIFFAREA 0.445500 ;
    PORT
      LAYER met2 ;
        RECT 273.790 696.000 274.070 700.000 ;
    END
  END tl_o[13]
  PIN tl_o[14]
    DIRECTION OUTPUT ;
    USE SIGNAL ;
    ANTENNADIFFAREA 0.445500 ;
    PORT
      LAYER met2 ;
        RECT 138.550 696.000 138.830 700.000 ;
    END
  END tl_o[14]
  PIN tl_o[15]
    DIRECTION OUTPUT ;
    USE SIGNAL ;
    PORT
      LAYER met2 ;
        RECT 41.950 696.000 42.230 700.000 ;
    END
  END tl_o[15]
  PIN tl_o[16]
    DIRECTION OUTPUT ;
    USE SIGNAL ;
    ANTENNADIFFAREA 0.445500 ;
    PORT
      LAYER met3 ;
        RECT 696.000 380.840 700.000 381.440 ;
    END
  END tl_o[16]
  PIN tl_o[17]
    DIRECTION OUTPUT ;
    USE SIGNAL ;
    ANTENNADIFFAREA 0.445500 ;
    PORT
      LAYER met3 ;
        RECT 696.000 394.440 700.000 395.040 ;
    END
  END tl_o[17]
  PIN tl_o[18]
    DIRECTION OUTPUT ;
    USE SIGNAL ;
    ANTENNADIFFAREA 0.445500 ;
    PORT
      LAYER met3 ;
        RECT 696.000 367.240 700.000 367.840 ;
    END
  END tl_o[18]
  PIN tl_o[19]
    DIRECTION OUTPUT ;
    USE SIGNAL ;
    ANTENNADIFFAREA 0.445500 ;
    PORT
      LAYER met3 ;
        RECT 696.000 374.040 700.000 374.640 ;
    END
  END tl_o[19]
  PIN tl_o[1]
    DIRECTION OUTPUT ;
    USE SIGNAL ;
    ANTENNADIFFAREA 0.445500 ;
    PORT
      LAYER met2 ;
        RECT 293.110 696.000 293.390 700.000 ;
    END
  END tl_o[1]
  PIN tl_o[20]
    DIRECTION OUTPUT ;
    USE SIGNAL ;
    ANTENNADIFFAREA 0.445500 ;
    PORT
      LAYER met3 ;
        RECT 696.000 387.640 700.000 388.240 ;
    END
  END tl_o[20]
  PIN tl_o[21]
    DIRECTION OUTPUT ;
    USE SIGNAL ;
    ANTENNADIFFAREA 0.445500 ;
    PORT
      LAYER met3 ;
        RECT 696.000 384.240 700.000 384.840 ;
    END
  END tl_o[21]
  PIN tl_o[22]
    DIRECTION OUTPUT ;
    USE SIGNAL ;
    ANTENNADIFFAREA 0.445500 ;
    PORT
      LAYER met3 ;
        RECT 696.000 391.040 700.000 391.640 ;
    END
  END tl_o[22]
  PIN tl_o[23]
    DIRECTION OUTPUT ;
    USE SIGNAL ;
    ANTENNADIFFAREA 0.445500 ;
    PORT
      LAYER met3 ;
        RECT 696.000 363.840 700.000 364.440 ;
    END
  END tl_o[23]
  PIN tl_o[24]
    DIRECTION OUTPUT ;
    USE SIGNAL ;
    ANTENNADIFFAREA 0.445500 ;
    PORT
      LAYER met3 ;
        RECT 696.000 431.840 700.000 432.440 ;
    END
  END tl_o[24]
  PIN tl_o[25]
    DIRECTION OUTPUT ;
    USE SIGNAL ;
    ANTENNADIFFAREA 0.445500 ;
    PORT
      LAYER met3 ;
        RECT 696.000 411.440 700.000 412.040 ;
    END
  END tl_o[25]
  PIN tl_o[26]
    DIRECTION OUTPUT ;
    USE SIGNAL ;
    ANTENNADIFFAREA 0.445500 ;
    PORT
      LAYER met3 ;
        RECT 696.000 425.040 700.000 425.640 ;
    END
  END tl_o[26]
  PIN tl_o[27]
    DIRECTION OUTPUT ;
    USE SIGNAL ;
    ANTENNADIFFAREA 0.445500 ;
    PORT
      LAYER met3 ;
        RECT 696.000 418.240 700.000 418.840 ;
    END
  END tl_o[27]
  PIN tl_o[28]
    DIRECTION OUTPUT ;
    USE SIGNAL ;
    ANTENNADIFFAREA 0.445500 ;
    PORT
      LAYER met3 ;
        RECT 696.000 435.240 700.000 435.840 ;
    END
  END tl_o[28]
  PIN tl_o[29]
    DIRECTION OUTPUT ;
    USE SIGNAL ;
    ANTENNADIFFAREA 0.445500 ;
    PORT
      LAYER met3 ;
        RECT 696.000 465.840 700.000 466.440 ;
    END
  END tl_o[29]
  PIN tl_o[2]
    DIRECTION OUTPUT ;
    USE SIGNAL ;
    ANTENNADIFFAREA 0.445500 ;
    PORT
      LAYER met3 ;
        RECT 696.000 421.640 700.000 422.240 ;
    END
  END tl_o[2]
  PIN tl_o[30]
    DIRECTION OUTPUT ;
    USE SIGNAL ;
    ANTENNADIFFAREA 0.445500 ;
    PORT
      LAYER met3 ;
        RECT 696.000 452.240 700.000 452.840 ;
    END
  END tl_o[30]
  PIN tl_o[31]
    DIRECTION OUTPUT ;
    USE SIGNAL ;
    ANTENNADIFFAREA 0.445500 ;
    PORT
      LAYER met3 ;
        RECT 696.000 462.440 700.000 463.040 ;
    END
  END tl_o[31]
  PIN tl_o[32]
    DIRECTION OUTPUT ;
    USE SIGNAL ;
    ANTENNADIFFAREA 0.445500 ;
    PORT
      LAYER met3 ;
        RECT 696.000 438.640 700.000 439.240 ;
    END
  END tl_o[32]
  PIN tl_o[33]
    DIRECTION OUTPUT ;
    USE SIGNAL ;
    ANTENNADIFFAREA 0.445500 ;
    PORT
      LAYER met3 ;
        RECT 696.000 445.440 700.000 446.040 ;
    END
  END tl_o[33]
  PIN tl_o[34]
    DIRECTION OUTPUT ;
    USE SIGNAL ;
    ANTENNADIFFAREA 0.445500 ;
    PORT
      LAYER met3 ;
        RECT 696.000 476.040 700.000 476.640 ;
    END
  END tl_o[34]
  PIN tl_o[35]
    DIRECTION OUTPUT ;
    USE SIGNAL ;
    ANTENNADIFFAREA 0.445500 ;
    PORT
      LAYER met3 ;
        RECT 696.000 459.040 700.000 459.640 ;
    END
  END tl_o[35]
  PIN tl_o[36]
    DIRECTION OUTPUT ;
    USE SIGNAL ;
    ANTENNADIFFAREA 0.445500 ;
    PORT
      LAYER met3 ;
        RECT 696.000 472.640 700.000 473.240 ;
    END
  END tl_o[36]
  PIN tl_o[37]
    DIRECTION OUTPUT ;
    USE SIGNAL ;
    ANTENNADIFFAREA 0.445500 ;
    PORT
      LAYER met3 ;
        RECT 696.000 455.640 700.000 456.240 ;
    END
  END tl_o[37]
  PIN tl_o[38]
    DIRECTION OUTPUT ;
    USE SIGNAL ;
    ANTENNADIFFAREA 0.445500 ;
    PORT
      LAYER met3 ;
        RECT 696.000 469.240 700.000 469.840 ;
    END
  END tl_o[38]
  PIN tl_o[39]
    DIRECTION OUTPUT ;
    USE SIGNAL ;
    ANTENNADIFFAREA 0.445500 ;
    PORT
      LAYER met3 ;
        RECT 696.000 499.840 700.000 500.440 ;
    END
  END tl_o[39]
  PIN tl_o[3]
    DIRECTION OUTPUT ;
    USE SIGNAL ;
    ANTENNADIFFAREA 0.445500 ;
    PORT
      LAYER met3 ;
        RECT 696.000 442.040 700.000 442.640 ;
    END
  END tl_o[3]
  PIN tl_o[40]
    DIRECTION OUTPUT ;
    USE SIGNAL ;
    ANTENNADIFFAREA 0.445500 ;
    PORT
      LAYER met3 ;
        RECT 696.000 503.240 700.000 503.840 ;
    END
  END tl_o[40]
  PIN tl_o[41]
    DIRECTION OUTPUT ;
    USE SIGNAL ;
    ANTENNADIFFAREA 0.445500 ;
    PORT
      LAYER met3 ;
        RECT 696.000 486.240 700.000 486.840 ;
    END
  END tl_o[41]
  PIN tl_o[42]
    DIRECTION OUTPUT ;
    USE SIGNAL ;
    ANTENNADIFFAREA 0.445500 ;
    PORT
      LAYER met3 ;
        RECT 696.000 493.040 700.000 493.640 ;
    END
  END tl_o[42]
  PIN tl_o[43]
    DIRECTION OUTPUT ;
    USE SIGNAL ;
    ANTENNADIFFAREA 0.445500 ;
    PORT
      LAYER met3 ;
        RECT 696.000 482.840 700.000 483.440 ;
    END
  END tl_o[43]
  PIN tl_o[44]
    DIRECTION OUTPUT ;
    USE SIGNAL ;
    ANTENNADIFFAREA 0.445500 ;
    PORT
      LAYER met3 ;
        RECT 696.000 479.440 700.000 480.040 ;
    END
  END tl_o[44]
  PIN tl_o[45]
    DIRECTION OUTPUT ;
    USE SIGNAL ;
    ANTENNADIFFAREA 0.445500 ;
    PORT
      LAYER met3 ;
        RECT 696.000 489.640 700.000 490.240 ;
    END
  END tl_o[45]
  PIN tl_o[46]
    DIRECTION OUTPUT ;
    USE SIGNAL ;
    ANTENNADIFFAREA 0.445500 ;
    PORT
      LAYER met3 ;
        RECT 696.000 496.440 700.000 497.040 ;
    END
  END tl_o[46]
  PIN tl_o[47]
    DIRECTION OUTPUT ;
    USE SIGNAL ;
    ANTENNADIFFAREA 0.445500 ;
    PORT
      LAYER met3 ;
        RECT 696.000 506.640 700.000 507.240 ;
    END
  END tl_o[47]
  PIN tl_o[48]
    DIRECTION OUTPUT ;
    USE SIGNAL ;
    PORT
      LAYER met2 ;
        RECT 177.190 696.000 177.470 700.000 ;
    END
  END tl_o[48]
  PIN tl_o[49]
    DIRECTION OUTPUT ;
    USE SIGNAL ;
    ANTENNADIFFAREA 0.445500 ;
    PORT
      LAYER met2 ;
        RECT 164.310 696.000 164.590 700.000 ;
    END
  END tl_o[49]
  PIN tl_o[4]
    DIRECTION OUTPUT ;
    USE SIGNAL ;
    ANTENNADIFFAREA 0.445500 ;
    PORT
      LAYER met3 ;
        RECT 696.000 414.840 700.000 415.440 ;
    END
  END tl_o[4]
  PIN tl_o[50]
    DIRECTION OUTPUT ;
    USE SIGNAL ;
    ANTENNADIFFAREA 0.445500 ;
    PORT
      LAYER met2 ;
        RECT 186.850 696.000 187.130 700.000 ;
    END
  END tl_o[50]
  PIN tl_o[51]
    DIRECTION OUTPUT ;
    USE SIGNAL ;
    ANTENNADIFFAREA 0.445500 ;
    PORT
      LAYER met2 ;
        RECT 199.730 696.000 200.010 700.000 ;
    END
  END tl_o[51]
  PIN tl_o[52]
    DIRECTION OUTPUT ;
    USE SIGNAL ;
    ANTENNADIFFAREA 0.445500 ;
    PORT
      LAYER met2 ;
        RECT 161.090 696.000 161.370 700.000 ;
    END
  END tl_o[52]
  PIN tl_o[53]
    DIRECTION OUTPUT ;
    USE SIGNAL ;
    ANTENNADIFFAREA 0.445500 ;
    PORT
      LAYER met2 ;
        RECT 241.590 696.000 241.870 700.000 ;
    END
  END tl_o[53]
  PIN tl_o[54]
    DIRECTION OUTPUT ;
    USE SIGNAL ;
    ANTENNADIFFAREA 0.445500 ;
    PORT
      LAYER met2 ;
        RECT 219.050 696.000 219.330 700.000 ;
    END
  END tl_o[54]
  PIN tl_o[55]
    DIRECTION OUTPUT ;
    USE SIGNAL ;
    ANTENNADIFFAREA 0.445500 ;
    PORT
      LAYER met2 ;
        RECT 270.570 696.000 270.850 700.000 ;
    END
  END tl_o[55]
  PIN tl_o[56]
    DIRECTION OUTPUT ;
    USE SIGNAL ;
    ANTENNADIFFAREA 0.445500 ;
    PORT
      LAYER met2 ;
        RECT 264.130 696.000 264.410 700.000 ;
    END
  END tl_o[56]
  PIN tl_o[57]
    DIRECTION OUTPUT ;
    USE SIGNAL ;
    ANTENNADIFFAREA 0.445500 ;
    PORT
      LAYER met2 ;
        RECT 286.670 696.000 286.950 700.000 ;
    END
  END tl_o[57]
  PIN tl_o[58]
    DIRECTION OUTPUT ;
    USE SIGNAL ;
    ANTENNADIFFAREA 0.445500 ;
    PORT
      LAYER met2 ;
        RECT 280.230 696.000 280.510 700.000 ;
    END
  END tl_o[58]
  PIN tl_o[59]
    DIRECTION OUTPUT ;
    USE SIGNAL ;
    PORT
      LAYER met2 ;
        RECT 685.950 0.000 686.230 4.000 ;
    END
  END tl_o[59]
  PIN tl_o[5]
    DIRECTION OUTPUT ;
    USE SIGNAL ;
    ANTENNADIFFAREA 0.445500 ;
    PORT
      LAYER met3 ;
        RECT 696.000 404.640 700.000 405.240 ;
    END
  END tl_o[5]
  PIN tl_o[60]
    DIRECTION OUTPUT ;
    USE SIGNAL ;
    PORT
      LAYER met2 ;
        RECT 16.190 696.000 16.470 700.000 ;
    END
  END tl_o[60]
  PIN tl_o[61]
    DIRECTION OUTPUT ;
    USE SIGNAL ;
    PORT
      LAYER met2 ;
        RECT 51.610 0.000 51.890 4.000 ;
    END
  END tl_o[61]
  PIN tl_o[62]
    DIRECTION OUTPUT ;
    USE SIGNAL ;
    ANTENNADIFFAREA 0.445500 ;
    PORT
      LAYER met2 ;
        RECT 289.890 696.000 290.170 700.000 ;
    END
  END tl_o[62]
  PIN tl_o[63]
    DIRECTION OUTPUT ;
    USE SIGNAL ;
    PORT
      LAYER met2 ;
        RECT 12.970 0.000 13.250 4.000 ;
    END
  END tl_o[63]
  PIN tl_o[64]
    DIRECTION OUTPUT ;
    USE SIGNAL ;
    PORT
      LAYER met2 ;
        RECT 682.730 0.000 683.010 4.000 ;
    END
  END tl_o[64]
  PIN tl_o[65]
    DIRECTION OUTPUT ;
    USE SIGNAL ;
    ANTENNADIFFAREA 0.445500 ;
    PORT
      LAYER met2 ;
        RECT 338.190 696.000 338.470 700.000 ;
    END
  END tl_o[65]
  PIN tl_o[6]
    DIRECTION OUTPUT ;
    USE SIGNAL ;
    ANTENNADIFFAREA 0.445500 ;
    PORT
      LAYER met3 ;
        RECT 696.000 408.040 700.000 408.640 ;
    END
  END tl_o[6]
  PIN tl_o[7]
    DIRECTION OUTPUT ;
    USE SIGNAL ;
    ANTENNADIFFAREA 0.445500 ;
    PORT
      LAYER met3 ;
        RECT 696.000 428.440 700.000 429.040 ;
    END
  END tl_o[7]
  PIN tl_o[8]
    DIRECTION OUTPUT ;
    USE SIGNAL ;
    ANTENNADIFFAREA 0.445500 ;
    PORT
      LAYER met3 ;
        RECT 696.000 448.840 700.000 449.440 ;
    END
  END tl_o[8]
  PIN tl_o[9]
    DIRECTION OUTPUT ;
    USE SIGNAL ;
    ANTENNADIFFAREA 0.445500 ;
    PORT
      LAYER met2 ;
        RECT 148.210 696.000 148.490 700.000 ;
    END
  END tl_o[9]
  OBS
      LAYER nwell ;
        RECT 5.330 10.795 694.330 688.350 ;
      LAYER li1 ;
        RECT 5.520 10.795 694.140 688.245 ;
      LAYER met1 ;
        RECT 4.210 10.640 694.140 689.820 ;
      LAYER met2 ;
        RECT 4.230 695.720 9.470 697.525 ;
        RECT 10.310 695.720 12.690 697.525 ;
        RECT 13.530 695.720 15.910 697.525 ;
        RECT 16.750 695.720 19.130 697.525 ;
        RECT 19.970 695.720 22.350 697.525 ;
        RECT 23.190 695.720 25.570 697.525 ;
        RECT 26.410 695.720 28.790 697.525 ;
        RECT 29.630 695.720 32.010 697.525 ;
        RECT 32.850 695.720 35.230 697.525 ;
        RECT 36.070 695.720 38.450 697.525 ;
        RECT 39.290 695.720 41.670 697.525 ;
        RECT 42.510 695.720 44.890 697.525 ;
        RECT 45.730 695.720 48.110 697.525 ;
        RECT 48.950 695.720 51.330 697.525 ;
        RECT 52.170 695.720 54.550 697.525 ;
        RECT 55.390 695.720 135.050 697.525 ;
        RECT 135.890 695.720 138.270 697.525 ;
        RECT 139.110 695.720 141.490 697.525 ;
        RECT 142.330 695.720 144.710 697.525 ;
        RECT 145.550 695.720 147.930 697.525 ;
        RECT 148.770 695.720 151.150 697.525 ;
        RECT 151.990 695.720 154.370 697.525 ;
        RECT 155.210 695.720 157.590 697.525 ;
        RECT 158.430 695.720 160.810 697.525 ;
        RECT 161.650 695.720 164.030 697.525 ;
        RECT 164.870 695.720 167.250 697.525 ;
        RECT 168.090 695.720 170.470 697.525 ;
        RECT 171.310 695.720 173.690 697.525 ;
        RECT 174.530 695.720 176.910 697.525 ;
        RECT 177.750 695.720 180.130 697.525 ;
        RECT 180.970 695.720 183.350 697.525 ;
        RECT 184.190 695.720 186.570 697.525 ;
        RECT 187.410 695.720 189.790 697.525 ;
        RECT 190.630 695.720 193.010 697.525 ;
        RECT 193.850 695.720 196.230 697.525 ;
        RECT 197.070 695.720 199.450 697.525 ;
        RECT 200.290 695.720 202.670 697.525 ;
        RECT 203.510 695.720 205.890 697.525 ;
        RECT 206.730 695.720 209.110 697.525 ;
        RECT 209.950 695.720 212.330 697.525 ;
        RECT 213.170 695.720 215.550 697.525 ;
        RECT 216.390 695.720 218.770 697.525 ;
        RECT 219.610 695.720 221.990 697.525 ;
        RECT 222.830 695.720 225.210 697.525 ;
        RECT 226.050 695.720 228.430 697.525 ;
        RECT 229.270 695.720 231.650 697.525 ;
        RECT 232.490 695.720 234.870 697.525 ;
        RECT 235.710 695.720 238.090 697.525 ;
        RECT 238.930 695.720 241.310 697.525 ;
        RECT 242.150 695.720 244.530 697.525 ;
        RECT 245.370 695.720 247.750 697.525 ;
        RECT 248.590 695.720 250.970 697.525 ;
        RECT 251.810 695.720 254.190 697.525 ;
        RECT 255.030 695.720 257.410 697.525 ;
        RECT 258.250 695.720 260.630 697.525 ;
        RECT 261.470 695.720 263.850 697.525 ;
        RECT 264.690 695.720 267.070 697.525 ;
        RECT 267.910 695.720 270.290 697.525 ;
        RECT 271.130 695.720 273.510 697.525 ;
        RECT 274.350 695.720 276.730 697.525 ;
        RECT 277.570 695.720 279.950 697.525 ;
        RECT 280.790 695.720 283.170 697.525 ;
        RECT 284.010 695.720 286.390 697.525 ;
        RECT 287.230 695.720 289.610 697.525 ;
        RECT 290.450 695.720 292.830 697.525 ;
        RECT 293.670 695.720 296.050 697.525 ;
        RECT 296.890 695.720 299.270 697.525 ;
        RECT 300.110 695.720 302.490 697.525 ;
        RECT 303.330 695.720 305.710 697.525 ;
        RECT 306.550 695.720 308.930 697.525 ;
        RECT 309.770 695.720 312.150 697.525 ;
        RECT 312.990 695.720 315.370 697.525 ;
        RECT 316.210 695.720 318.590 697.525 ;
        RECT 319.430 695.720 321.810 697.525 ;
        RECT 322.650 695.720 325.030 697.525 ;
        RECT 325.870 695.720 328.250 697.525 ;
        RECT 329.090 695.720 331.470 697.525 ;
        RECT 332.310 695.720 334.690 697.525 ;
        RECT 335.530 695.720 337.910 697.525 ;
        RECT 338.750 695.720 341.130 697.525 ;
        RECT 341.970 695.720 344.350 697.525 ;
        RECT 345.190 695.720 347.570 697.525 ;
        RECT 348.410 695.720 350.790 697.525 ;
        RECT 351.630 695.720 354.010 697.525 ;
        RECT 354.850 695.720 357.230 697.525 ;
        RECT 358.070 695.720 360.450 697.525 ;
        RECT 361.290 695.720 363.670 697.525 ;
        RECT 364.510 695.720 366.890 697.525 ;
        RECT 367.730 695.720 370.110 697.525 ;
        RECT 370.950 695.720 373.330 697.525 ;
        RECT 374.170 695.720 376.550 697.525 ;
        RECT 377.390 695.720 379.770 697.525 ;
        RECT 380.610 695.720 382.990 697.525 ;
        RECT 383.830 695.720 386.210 697.525 ;
        RECT 387.050 695.720 389.430 697.525 ;
        RECT 390.270 695.720 392.650 697.525 ;
        RECT 393.490 695.720 395.870 697.525 ;
        RECT 396.710 695.720 399.090 697.525 ;
        RECT 399.930 695.720 402.310 697.525 ;
        RECT 403.150 695.720 405.530 697.525 ;
        RECT 406.370 695.720 408.750 697.525 ;
        RECT 409.590 695.720 411.970 697.525 ;
        RECT 412.810 695.720 415.190 697.525 ;
        RECT 416.030 695.720 418.410 697.525 ;
        RECT 419.250 695.720 421.630 697.525 ;
        RECT 422.470 695.720 424.850 697.525 ;
        RECT 425.690 695.720 428.070 697.525 ;
        RECT 428.910 695.720 431.290 697.525 ;
        RECT 432.130 695.720 434.510 697.525 ;
        RECT 435.350 695.720 437.730 697.525 ;
        RECT 438.570 695.720 440.950 697.525 ;
        RECT 441.790 695.720 444.170 697.525 ;
        RECT 445.010 695.720 447.390 697.525 ;
        RECT 448.230 695.720 450.610 697.525 ;
        RECT 451.450 695.720 453.830 697.525 ;
        RECT 454.670 695.720 457.050 697.525 ;
        RECT 457.890 695.720 460.270 697.525 ;
        RECT 461.110 695.720 463.490 697.525 ;
        RECT 464.330 695.720 466.710 697.525 ;
        RECT 467.550 695.720 469.930 697.525 ;
        RECT 470.770 695.720 473.150 697.525 ;
        RECT 473.990 695.720 476.370 697.525 ;
        RECT 477.210 695.720 479.590 697.525 ;
        RECT 480.430 695.720 482.810 697.525 ;
        RECT 483.650 695.720 486.030 697.525 ;
        RECT 486.870 695.720 489.250 697.525 ;
        RECT 490.090 695.720 492.470 697.525 ;
        RECT 493.310 695.720 495.690 697.525 ;
        RECT 496.530 695.720 498.910 697.525 ;
        RECT 499.750 695.720 502.130 697.525 ;
        RECT 502.970 695.720 505.350 697.525 ;
        RECT 506.190 695.720 508.570 697.525 ;
        RECT 509.410 695.720 511.790 697.525 ;
        RECT 512.630 695.720 515.010 697.525 ;
        RECT 515.850 695.720 518.230 697.525 ;
        RECT 519.070 695.720 521.450 697.525 ;
        RECT 522.290 695.720 524.670 697.525 ;
        RECT 525.510 695.720 527.890 697.525 ;
        RECT 528.730 695.720 531.110 697.525 ;
        RECT 531.950 695.720 534.330 697.525 ;
        RECT 535.170 695.720 537.550 697.525 ;
        RECT 538.390 695.720 540.770 697.525 ;
        RECT 541.610 695.720 543.990 697.525 ;
        RECT 544.830 695.720 547.210 697.525 ;
        RECT 548.050 695.720 550.430 697.525 ;
        RECT 551.270 695.720 553.650 697.525 ;
        RECT 554.490 695.720 556.870 697.525 ;
        RECT 557.710 695.720 560.090 697.525 ;
        RECT 560.930 695.720 563.310 697.525 ;
        RECT 564.150 695.720 566.530 697.525 ;
        RECT 567.370 695.720 569.750 697.525 ;
        RECT 570.590 695.720 572.970 697.525 ;
        RECT 573.810 695.720 576.190 697.525 ;
        RECT 577.030 695.720 579.410 697.525 ;
        RECT 580.250 695.720 679.230 697.525 ;
        RECT 680.070 695.720 682.450 697.525 ;
        RECT 683.290 695.720 685.670 697.525 ;
        RECT 686.510 695.720 692.210 697.525 ;
        RECT 4.230 4.280 692.210 695.720 ;
        RECT 4.230 0.155 6.250 4.280 ;
        RECT 7.090 0.155 9.470 4.280 ;
        RECT 10.310 0.155 12.690 4.280 ;
        RECT 13.530 0.155 15.910 4.280 ;
        RECT 16.750 0.155 19.130 4.280 ;
        RECT 19.970 0.155 22.350 4.280 ;
        RECT 23.190 0.155 25.570 4.280 ;
        RECT 26.410 0.155 28.790 4.280 ;
        RECT 29.630 0.155 32.010 4.280 ;
        RECT 32.850 0.155 35.230 4.280 ;
        RECT 36.070 0.155 38.450 4.280 ;
        RECT 39.290 0.155 41.670 4.280 ;
        RECT 42.510 0.155 44.890 4.280 ;
        RECT 45.730 0.155 48.110 4.280 ;
        RECT 48.950 0.155 51.330 4.280 ;
        RECT 52.170 0.155 54.550 4.280 ;
        RECT 55.390 0.155 57.770 4.280 ;
        RECT 58.610 0.155 60.990 4.280 ;
        RECT 61.830 0.155 70.650 4.280 ;
        RECT 71.490 0.155 99.630 4.280 ;
        RECT 100.470 0.155 147.930 4.280 ;
        RECT 148.770 0.155 154.370 4.280 ;
        RECT 155.210 0.155 180.130 4.280 ;
        RECT 180.970 0.155 199.450 4.280 ;
        RECT 200.290 0.155 250.970 4.280 ;
        RECT 251.810 0.155 267.070 4.280 ;
        RECT 267.910 0.155 643.810 4.280 ;
        RECT 644.650 0.155 647.030 4.280 ;
        RECT 647.870 0.155 650.250 4.280 ;
        RECT 651.090 0.155 653.470 4.280 ;
        RECT 654.310 0.155 656.690 4.280 ;
        RECT 657.530 0.155 659.910 4.280 ;
        RECT 660.750 0.155 679.230 4.280 ;
        RECT 680.070 0.155 682.450 4.280 ;
        RECT 683.290 0.155 685.670 4.280 ;
        RECT 686.510 0.155 692.210 4.280 ;
      LAYER met3 ;
        RECT 3.990 696.640 695.600 697.505 ;
        RECT 3.990 694.640 696.000 696.640 ;
        RECT 3.990 693.240 695.600 694.640 ;
        RECT 3.990 691.240 696.000 693.240 ;
        RECT 3.990 689.840 695.600 691.240 ;
        RECT 3.990 687.840 696.000 689.840 ;
        RECT 3.990 686.440 695.600 687.840 ;
        RECT 3.990 684.440 696.000 686.440 ;
        RECT 3.990 683.040 695.600 684.440 ;
        RECT 3.990 681.040 696.000 683.040 ;
        RECT 3.990 679.640 695.600 681.040 ;
        RECT 3.990 609.640 696.000 679.640 ;
        RECT 3.990 608.240 695.600 609.640 ;
        RECT 3.990 599.440 696.000 608.240 ;
        RECT 4.400 598.040 696.000 599.440 ;
        RECT 3.990 585.840 696.000 598.040 ;
        RECT 3.990 584.440 695.600 585.840 ;
        RECT 3.990 558.640 696.000 584.440 ;
        RECT 3.990 557.240 695.600 558.640 ;
        RECT 3.990 507.640 696.000 557.240 ;
        RECT 3.990 506.240 695.600 507.640 ;
        RECT 3.990 504.240 696.000 506.240 ;
        RECT 3.990 502.840 695.600 504.240 ;
        RECT 3.990 500.840 696.000 502.840 ;
        RECT 3.990 499.440 695.600 500.840 ;
        RECT 3.990 497.440 696.000 499.440 ;
        RECT 3.990 496.040 695.600 497.440 ;
        RECT 3.990 494.040 696.000 496.040 ;
        RECT 3.990 492.640 695.600 494.040 ;
        RECT 3.990 490.640 696.000 492.640 ;
        RECT 3.990 489.240 695.600 490.640 ;
        RECT 3.990 487.240 696.000 489.240 ;
        RECT 3.990 485.840 695.600 487.240 ;
        RECT 3.990 483.840 696.000 485.840 ;
        RECT 3.990 482.440 695.600 483.840 ;
        RECT 3.990 480.440 696.000 482.440 ;
        RECT 3.990 479.040 695.600 480.440 ;
        RECT 3.990 477.040 696.000 479.040 ;
        RECT 3.990 475.640 695.600 477.040 ;
        RECT 3.990 473.640 696.000 475.640 ;
        RECT 3.990 472.240 695.600 473.640 ;
        RECT 3.990 470.240 696.000 472.240 ;
        RECT 3.990 468.840 695.600 470.240 ;
        RECT 3.990 466.840 696.000 468.840 ;
        RECT 3.990 465.440 695.600 466.840 ;
        RECT 3.990 463.440 696.000 465.440 ;
        RECT 3.990 462.040 695.600 463.440 ;
        RECT 3.990 460.040 696.000 462.040 ;
        RECT 3.990 458.640 695.600 460.040 ;
        RECT 3.990 456.640 696.000 458.640 ;
        RECT 3.990 455.240 695.600 456.640 ;
        RECT 3.990 453.240 696.000 455.240 ;
        RECT 3.990 451.840 695.600 453.240 ;
        RECT 3.990 449.840 696.000 451.840 ;
        RECT 3.990 448.440 695.600 449.840 ;
        RECT 3.990 446.440 696.000 448.440 ;
        RECT 3.990 445.040 695.600 446.440 ;
        RECT 3.990 443.040 696.000 445.040 ;
        RECT 3.990 441.640 695.600 443.040 ;
        RECT 3.990 439.640 696.000 441.640 ;
        RECT 3.990 438.240 695.600 439.640 ;
        RECT 3.990 436.240 696.000 438.240 ;
        RECT 3.990 434.840 695.600 436.240 ;
        RECT 3.990 432.840 696.000 434.840 ;
        RECT 3.990 431.440 695.600 432.840 ;
        RECT 3.990 429.440 696.000 431.440 ;
        RECT 3.990 428.040 695.600 429.440 ;
        RECT 3.990 426.040 696.000 428.040 ;
        RECT 3.990 424.640 695.600 426.040 ;
        RECT 3.990 422.640 696.000 424.640 ;
        RECT 3.990 421.240 695.600 422.640 ;
        RECT 3.990 419.240 696.000 421.240 ;
        RECT 3.990 417.840 695.600 419.240 ;
        RECT 3.990 415.840 696.000 417.840 ;
        RECT 3.990 414.440 695.600 415.840 ;
        RECT 3.990 412.440 696.000 414.440 ;
        RECT 3.990 411.040 695.600 412.440 ;
        RECT 3.990 409.040 696.000 411.040 ;
        RECT 3.990 407.640 695.600 409.040 ;
        RECT 3.990 405.640 696.000 407.640 ;
        RECT 3.990 404.240 695.600 405.640 ;
        RECT 3.990 402.240 696.000 404.240 ;
        RECT 3.990 400.840 695.600 402.240 ;
        RECT 3.990 398.840 696.000 400.840 ;
        RECT 3.990 397.440 695.600 398.840 ;
        RECT 3.990 395.440 696.000 397.440 ;
        RECT 3.990 394.040 695.600 395.440 ;
        RECT 3.990 392.040 696.000 394.040 ;
        RECT 3.990 390.640 695.600 392.040 ;
        RECT 3.990 388.640 696.000 390.640 ;
        RECT 3.990 387.240 695.600 388.640 ;
        RECT 3.990 385.240 696.000 387.240 ;
        RECT 3.990 383.840 695.600 385.240 ;
        RECT 3.990 381.840 696.000 383.840 ;
        RECT 3.990 380.440 695.600 381.840 ;
        RECT 3.990 378.440 696.000 380.440 ;
        RECT 3.990 377.040 695.600 378.440 ;
        RECT 3.990 375.040 696.000 377.040 ;
        RECT 3.990 373.640 695.600 375.040 ;
        RECT 3.990 371.640 696.000 373.640 ;
        RECT 3.990 370.240 695.600 371.640 ;
        RECT 3.990 368.240 696.000 370.240 ;
        RECT 3.990 366.840 695.600 368.240 ;
        RECT 3.990 364.840 696.000 366.840 ;
        RECT 3.990 363.440 695.600 364.840 ;
        RECT 3.990 361.440 696.000 363.440 ;
        RECT 3.990 360.040 695.600 361.440 ;
        RECT 3.990 320.640 696.000 360.040 ;
        RECT 3.990 319.240 695.600 320.640 ;
        RECT 3.990 310.440 696.000 319.240 ;
        RECT 3.990 309.040 695.600 310.440 ;
        RECT 3.990 225.440 696.000 309.040 ;
        RECT 3.990 224.040 695.600 225.440 ;
        RECT 3.990 18.040 696.000 224.040 ;
        RECT 4.400 16.640 696.000 18.040 ;
        RECT 3.990 14.640 696.000 16.640 ;
        RECT 4.400 13.240 696.000 14.640 ;
        RECT 3.990 11.240 696.000 13.240 ;
        RECT 4.400 9.840 696.000 11.240 ;
        RECT 3.990 7.840 696.000 9.840 ;
        RECT 4.400 6.440 696.000 7.840 ;
        RECT 3.990 4.440 696.000 6.440 ;
        RECT 4.400 3.040 696.000 4.440 ;
        RECT 3.990 1.040 696.000 3.040 ;
        RECT 4.400 0.175 696.000 1.040 ;
      LAYER met4 ;
        RECT 111.615 70.215 174.240 636.985 ;
        RECT 176.640 70.215 177.540 636.985 ;
        RECT 179.940 70.215 327.840 636.985 ;
        RECT 330.240 70.215 331.140 636.985 ;
        RECT 333.540 70.215 481.440 636.985 ;
        RECT 483.840 70.215 484.740 636.985 ;
        RECT 487.140 70.215 623.465 636.985 ;
  END
END uart
END LIBRARY

